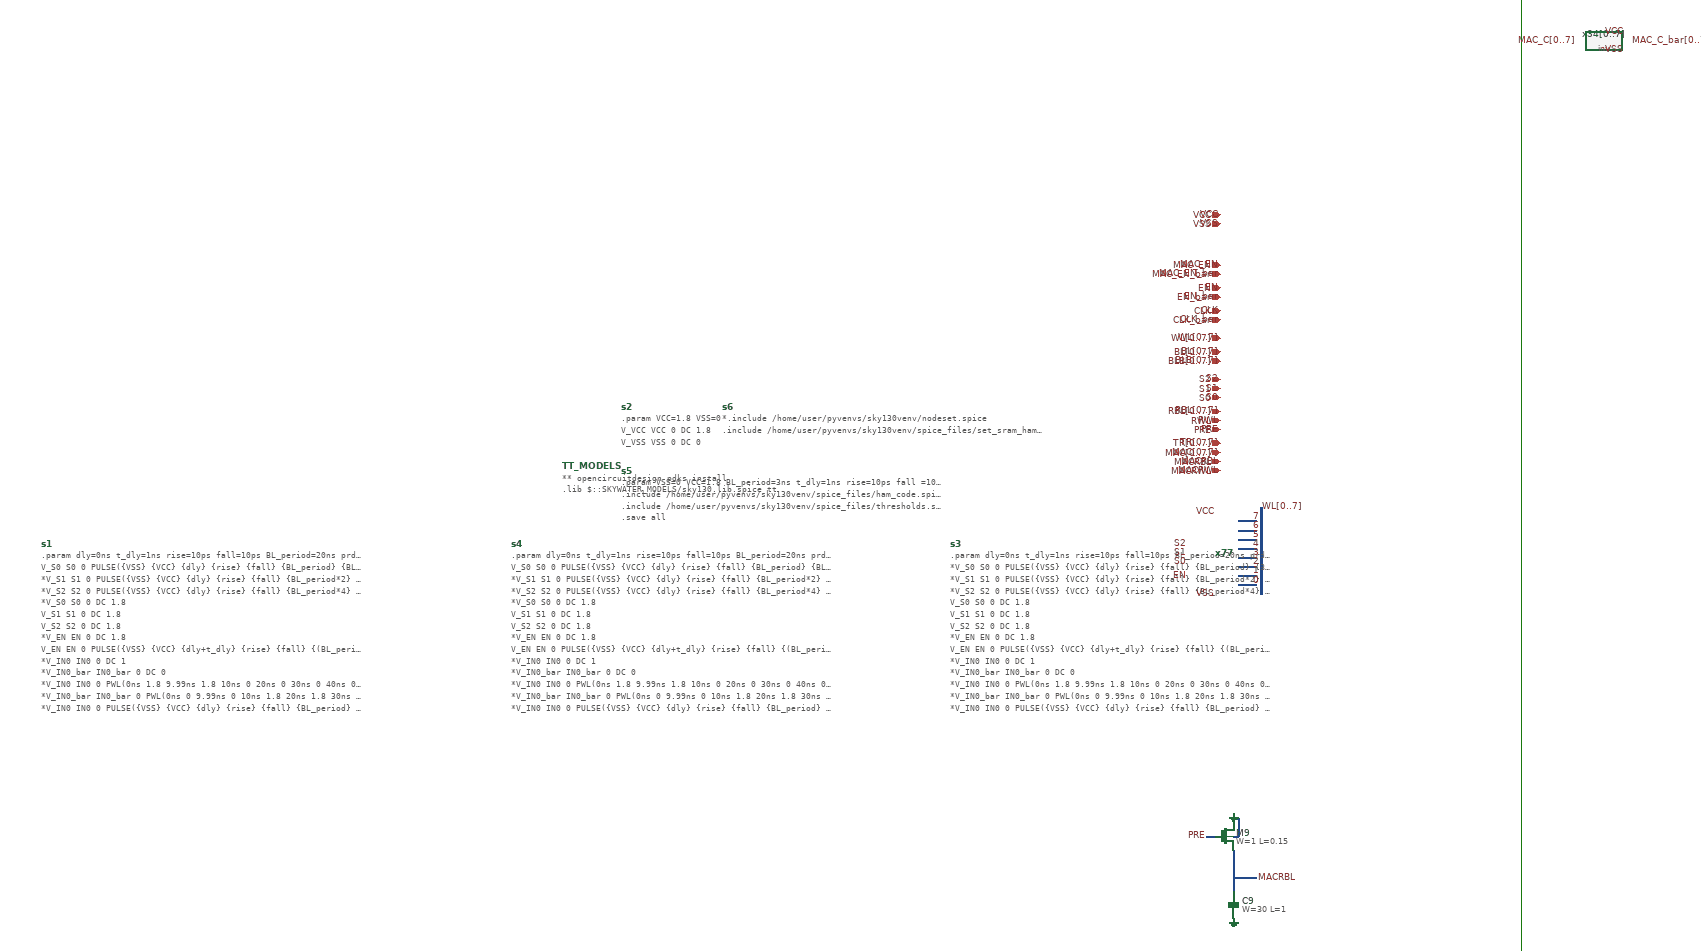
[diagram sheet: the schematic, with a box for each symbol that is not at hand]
v {xschem version=3.4.8RC file_version=1.3}
G {}
K {}
V {}
S {}
F {}
E {}
B 2 -940 -3380 -140 -2980 {flags=graph
y1=-0.027
y2=1.9
ypos1=0.4549552
ypos2=2.2583164
divy=5
subdivy=1
unity=1
x1=1.305e-08
x2=1.0005e-07
divx=5
subdivx=1
xlabmag=1.0
ylabmag=1.0
dataset=-1
unitx=1
logx=0
logy=0
rawfile=$netlist_dir/ham_real_PART1&2.raw
autoload=0
digital=1
legend=1
sim_type=tran
color="4 5 6 7 8 9 10 11 12 13 14 15 16 17 18 19 20"
node="en
pre
rwl
macrwl
clk
mac_en
ROW1;xsram8.q,xsram7.q,xsram6.q,xsram5.q,xsram4.q,xsram3.q,xsram2.q,xsram1.q
ROW2;xsram16.q,xsram15.q,xsram14.q,xsram13.q,xsram12.q,xsram11.q,xsram10.q,xsram9.q
ROW3;xsram24.q,xsram23.q,xsram22.q,xsram21.q,xsram20.q,xsram19.q,xsram18.q,xsram17.q
ROW4;xsram32.q,xsram31.q,xsram30.q,xsram29.q,xsram28.q,xsram27.q,xsram26.q,xsram25.q
ROW5;xsram40.q,xsram39.q,xsram38.q,xsram37.q,xsram36.q,xsram35.q,xsram34.q,xsram33.q
ROW6;xsram48.q,xsram47.q,xsram46.q,xsram45.q,xsram44.q,xsram43.q,xsram42.q,xsram41.q
ROW7;xsram56.q,xsram55.q,xsram54.q,xsram53.q,xsram52.q,xsram51.q,xsram50.q,xsram49.q
ROW8;xsram64.q,xsram63.q,xsram62.q,xsram61.q,xsram60.q,xsram59.q,xsram58.q,xsram57.q
ROW9;xsram_ham8.q,xsram_ham7.q,xsram_ham6.q,xsram_ham5.q,xsram_ham4.q,xsram_ham3.q,xsram_ham2.q,xsram_ham1.q
mac;mac_c7,mac_c6,mac_c5,mac_c4,mac_c3,mac_c2,mac_c1,mac_c0
mac_bar;mac_c_bar7,mac_c_bar6,mac_c_bar5,mac_c_bar4,mac_c_bar3,mac_c_bar2,mac_c_bar1,mac_c_bar0"}
B 2 -1760 -2440 -960 -2040 {flags=graph,unlocked
y1=-0.027
y2=1.9
ypos1=-0.027
ypos2=1.9
divy=5
subdivy=1
unity=1
x1=1.305e-08
x2=1.0005e-07
divx=5
subdivx=1
xlabmag=1.0
ylabmag=1.0
dataset=-1
unitx=1
logx=0
logy=0
rawfile=$netlist_dir/ham_real_PART1&2.raw
autoload=0
digital=1
color="4 5 6 7 8 9 10 11 7 7 7 7"
node="bl7
bl6
bl5
bl4
bl3
bl2
bl1
bl0


blb3
blb2
blb1
blb0"
hilight_wave=-1}
B 2 -1760 -2910 -960 -2510 {flags=graph
y1=0
y2=2
ypos1=0
ypos2=2
divy=5
subdivy=1
unity=1
x1=1.305e-08
x2=1.0005e-07
divx=5
subdivx=1
xlabmag=1.0
ylabmag=1.0
node="S;s2,s1,s0
en
pre
rwl
clk
mac_en
macrwl"
color="4 5 6 7 8 9 10"
dataset=-1
unitx=1
logx=0
logy=0
hilight_wave=4
digital=1
rawfile=$netlist_dir/ham_real_PART1&2.raw}
B 2 -1760 -3380 -960 -2980 {flags=graph
y1=-0.059
y2=1.9
ypos1=-0.027
ypos2=1.9
divy=5
subdivy=1
unity=1
x1=1.305e-08
x2=1.0005e-07
divx=5
subdivx=1
xlabmag=1.0
ylabmag=1.0
dataset=-1
unitx=1
logx=0
logy=0
rawfile=$netlist_dir/ham_real_PART1&2.raw
autoload=0
digital=1
hilight_wave=-1
sim_type=tran
color="4 7 7 9 9 6 6 11 11 5 5 8 8 20 20 21 21"
node="clk
x17.net1_1
x17.net1_0
x18.net1_1
x18.net1_0
x19.net1_1
x19.net1_0
x20.net1_1
x20.net1_0
x79.net1_1
x79.net1_0
x78.net1_1
x78.net1_0
x80.net1_1
x80.net1_0
x81.net1_1
x81.net1_0"}
B 2 -940 -2440 -140 -2040 {flags=graph
y1=-0.052
y2=1.9
ypos1=-0.027
ypos2=1.9
divy=5
subdivy=1
unity=1
x1=1.305e-08
x2=1.0005e-07
divx=5
subdivx=1
xlabmag=1.0
ylabmag=1.0
dataset=-1
unitx=1
logx=0
logy=0
rawfile=$netlist_dir/ham_real_PART1&2.raw
autoload=0
digital=1
hilight_wave=6
node="S;s2,s1,s0
en
pre
rwl
clk
mac_en
macrwl"
sim_type=tran
color="4 5 6 7 8 9 10"}
B 2 -930 -3810 -130 -3410 {flags=graph
y1=-0.31
y2=1.8
ypos1=-0.027
ypos2=1.9
divy=5
subdivy=1
unity=1
x1=1.305e-08
x2=1.0005e-07
divx=5
subdivx=1
xlabmag=1.0
ylabmag=1.0
dataset=-1
unitx=1
logx=0
logy=0
rawfile=$netlist_dir/ham_real_PART1&2.raw
autoload=0
digital=0
hilight_wave=0
sim_type=tran
color="4 5"
node="xmac_dec8.x1.x1.out+
xmac_dec8.x1.x1.out-"}
B 2 -940 -2910 -140 -2510 {flags=graph
y1=1.5728868
y2=1.9000425
ypos1=-0.027
ypos2=1.9
divy=5
subdivy=1
unity=1
x1=1.305e-08
x2=1.0005e-07
divx=5
subdivx=1
xlabmag=1.0
ylabmag=1.0
dataset=-1
unitx=1
logx=0
logy=0
rawfile=$netlist_dir/ham_real_PART1&2.raw
autoload=0
digital=0
hilight_wave=11
sim_type=tran
color="4 5 6 7 8 9 10 11 12 13 13 13 13 13 13 13 13 13"
node="rbl7
rbl6
rbl5
rbl4
rbl3
rbl2
rbl1
rbl0
macrbl
clk

tr7
tr6
tr5
tr4
tr3
tr2
tr1
tr0"}
B 2 -930 -4210 -130 -3810 {flags=graph
y1=-0.31
y2=1.8
ypos1=-0.027
ypos2=1.9
divy=5
subdivy=1
unity=1
x1=1.305e-08
x2=1.0005e-07
divx=5
subdivx=1
xlabmag=1.0
ylabmag=1.0
dataset=-1
unitx=1
logx=0
logy=0
rawfile=$netlist_dir/ham_real_PART1&2.raw
autoload=0
digital=0
hilight_wave=0
sim_type=tran
color="4 5"
node="xmac_dec8.x1.x2.out+
xmac_dec8.x1.x2.out-"}
B 4 770 -3310 3160 -200 {fill=false}
N 200 -1670 200 -1480 {lab=WL[0..7]
bus=true}
N 150 -1640 190 -1640 {lab=WL7}
N 150 -1620 190 -1620 {lab=WL6}
N 150 -1600 190 -1600 {lab=WL5}
N 150 -1580 190 -1580 {lab=WL4}
N 150 -1560 190 -1560 {lab=WL3}
N 150 -1540 190 -1540 {lab=WL2}
N 150 -1520 190 -1520 {lab=WL1}
N 150 -1500 190 -1500 {lab=WL0}
N 140 -920 140 -830 {lab=MACRBL}
N 140 -860 190 -860 {lab=MACRBL}
N 140 -1000 140 -980 {lab=GND}
N 140 -950 150 -950 {lab=GND}
N 150 -990 150 -950 {lab=GND}
N 140 -990 150 -990 {lab=GND}
N 80 -950 100 -950 {lab=PRE}
C {lab_pin.sym} 890 -2690 0 0 {name=p277 sig_type=std_logic lab=MAC_C[0..7]}
C {inv.sym} 950 -2690 0 0 {name=x34[0..7]}
C {lab_pin.sym} 950 -2710 0 1 {name=p278 sig_type=std_logic lab=VCC}
C {lab_pin.sym} 950 -2670 0 1 {name=p279 sig_type=std_logic lab=VSS}
C {lab_pin.sym} 1010 -2690 2 0 {name=p280 sig_type=std_logic lab=MAC_C_bar[0..7]}
C {iopin.sym} 110 -2040 0 0 {name=p7 lab=WL[0..7]}
C {lab_pin.sym} 110 -2040 0 0 {name=p18 sig_type=std_logic lab=WL[0..7]}
C {code.sym} -1330 -1760 0 0 {
name=TT_MODELS
only_toplevel=true
format="tcleval( @value )"
spice_ignore=false
value="
** opencircuitdesign pdks install
.lib $::SKYWATER_MODELS/sky130.lib.spice tt
"
spice_ignore=false
      }
C {code_shown.sym} -1200 -1890 0 0 {name=s2 only_toplevel=false spice_ignore=false value=
"
.param VCC=1.8 VSS=0

V_VCC VCC 0 DC 1.8
V_VSS VSS 0 DC 0
"}
C {iopin.sym} 110 -1950 0 0 {name=p69 lab=S2}
C {iopin.sym} 110 -1930 0 0 {name=p70 lab=S1}
C {iopin.sym} 110 -1910 0 0 {name=p71 lab=S0}
C {lab_pin.sym} 110 -1950 0 0 {name=p72 sig_type=std_logic lab=S2}
C {lab_pin.sym} 110 -1930 0 0 {name=p73 sig_type=std_logic lab=S1}
C {lab_pin.sym} 110 -1910 0 0 {name=p74 sig_type=std_logic lab=S0}
C {iopin.sym} 110 -2310 0 0 {name=p78 lab=VCC}
C {iopin.sym} 110 -2290 0 0 {name=p79 lab=VSS}
C {lab_pin.sym} 110 -2290 0 0 {name=p80 sig_type=std_logic lab=VSS}
C {lab_pin.sym} 110 -2310 0 0 {name=p81 sig_type=std_logic lab=VCC}
C {iopin.sym} 110 -2150 0 0 {name=p82 lab=EN}
C {lab_pin.sym} 110 -2150 0 0 {name=p83 sig_type=std_logic lab=EN}
C {code_shown.sym} -480 -1590 0 1 {name=s3 only_toplevel=false spice_ignore=true value=
"
.param dly=0ns t_dly=1ns rise=10ps fall=10ps BL_period=20ns prds=8 pre_time=6ns read_time=2ns write_delay=10ns 


*V_S0 S0 0 PULSE(\{VSS\} \{VCC\} \{dly\} \{rise\} \{fall\} \{BL_period\} \{BL_period*2\} \{prds\})
*V_S1 S1 0 PULSE(\{VSS\} \{VCC\} \{dly\} \{rise\} \{fall\} \{BL_period*2\} \{BL_period*4\} \{prds\})
*V_S2 S2 0 PULSE(\{VSS\} \{VCC\} \{dly\} \{rise\} \{fall\} \{BL_period*4\} \{BL_period*8\} \{prds\})

V_S0 S0 0 DC 1.8
V_S1 S1 0 DC 1.8
V_S2 S2 0 DC 1.8

*V_EN EN 0 DC 1.8
V_EN EN 0 PULSE(\{VSS\} \{VCC\} \{dly+t_dly\} \{rise\} \{fall\} \{(BL_period/2)-t_dly*2\} \{BL_period\} \{prds\})

*V_IN0 IN0 0 DC 1
*V_IN0_bar IN0_bar 0 DC 0
*V_IN0 IN0 0 PWL(0ns 1.8 9.99ns 1.8 10ns 0 20ns 0 30ns 0 40ns 0 50ns 0 60ns 0 69.99ns 0 70ns 1.8)
*V_IN0_bar IN0_bar 0 PWL(0ns 0 9.99ns 0 10ns 1.8 20ns 1.8 30ns 1.8 40ns 1.8 50ns 1.8 60ns 1.8 69.99ns 1.8 70ns 0)
*V_IN0 IN0 0 PULSE(\{VSS\} \{VCC\} \{dly\} \{rise\} \{fall\} \{BL_period\} \{BL_period*2\} \{prds\})
*V_IN0_bar IN0_bar 0 PULSE(\{VCC\} \{VSS\} \{dly\} \{rise\} \{fall\} \{BL_period\} \{BL_period*2\} \{prds\})

V_BL0 BLB0 0 PULSE(\{VSS\} \{VCC\} \{dly\} \{rise\} \{fall\} \{BL_period\} \{BL_period*2\} \{prds\})
V_BLB0 BL0 0 PULSE(\{VCC\} \{VSS\} \{dly\} \{rise\} \{fall\} \{BL_period\} \{BL_period*2\} \{prds\})

V_BL1 BLB1 0 PULSE(\{VSS\} \{VCC\} \{dly\} \{rise\} \{fall\} \{BL_period*2\} \{BL_period*4\} \{prds\})
V_BLB1 BL1 0 PULSE(\{VCC\} \{VSS\} \{dly\} \{rise\} \{fall\} \{BL_period*2\} \{BL_period*4\} \{prds\})

V_BL2 BLB2 0 PULSE(\{VSS\} \{VCC\} \{dly\} \{rise\} \{fall\} \{BL_period*4\} \{BL_period*8\} \{prds\})
V_BLB2 BL2 0 PULSE(\{VCC\} \{VSS\} \{dly\} \{rise\} \{fall\} \{BL_period*4\} \{BL_period*8\} \{prds\})

V_BL3 BLB3 0 PULSE(\{VSS\} \{VCC\} \{dly\} \{rise\} \{fall\} \{BL_period*8\} \{BL_period*16\} \{prds\})
V_BLB3 BL3 0 PULSE(\{VCC\} \{VSS\} \{dly\} \{rise\} \{fall\} \{BL_period*8\} \{BL_period*16\} \{prds\})

V_BL4 BLB4 0 PULSE(\{VSS\} \{VCC\} \{dly\} \{rise\} \{fall\} \{BL_period*16\} \{BL_period*32\} \{prds\})
V_BLB4 BL4 0 PULSE(\{VCC\} \{VSS\} \{dly\} \{rise\} \{fall\} \{BL_period*16\} \{BL_period*32\} \{prds\})

V_BL5 BLB5 0 PULSE(\{VSS\} \{VCC\} \{dly\} \{rise\} \{fall\} \{BL_period*32\} \{BL_period*64\} \{prds\})
V_BLB5 BL5 0 PULSE(\{VCC\} \{VSS\} \{dly\} \{rise\} \{fall\} \{BL_period*32\} \{BL_period*64\} \{prds\})

V_BL6 BLB6 0 PULSE(\{VSS\} \{VCC\} \{dly\} \{rise\} \{fall\} \{BL_period*64\} \{BL_period*128\} \{prds\})
V_BLB6 BL6 0 PULSE(\{VCC\} \{VSS\} \{dly\} \{rise\} \{fall\} \{BL_period*64\} \{BL_period*128\} \{prds\})

V_BL7 BLB7 0 PULSE(\{VSS\} \{VCC\} \{dly\} \{rise\} \{fall\} \{BL_period*128\} \{BL_period*256\} \{prds\})
V_BLB7 BL7 0 PULSE(\{VCC\} \{VSS\} \{dly\} \{rise\} \{fall\} \{BL_period*128\} \{BL_period*256\} \{prds\})



*V_RWL RWL 0 DC 1.8
*V_RBL RBL 0 DC 0
*V_RWL RWL 0 PULSE(\{VCC\} \{VSS\} \{write_delay+t_dly+pre_time+t_dly\} \{rise\} \{fall\} \{read_time\} \{BL_period\} \{prds\})
*V_PRE PRE 0 PULSE(\{VSS\} \{VCC\} \{write_delay+t_dly\} \{rise\} \{fall\} \{pre_time\} \{BL_period\} \{prds\})
V_RWL RWL 0 PULSE(\{VCC\} \{VSS\} \{dly + BL_period/2 + 7ns\} \{rise\} \{fall\} \{read_time\} \{BL_period\} \{prds*2\})
V_PRE PRE 0 PULSE(\{VSS\} \{VCC\} \{dly + BL_period/2\} \{rise\} \{fall\} \{pre_time\} \{BL_period\} \{prds*2\})

.tran 0.01ns \{BL_period*2*10\}
.save all

.control
run
plot Y0 Y1+2 Y2+4 Y3+6 Y4+8 Y5+10 Y6+12 Y7+14
plot EN
plot I0 I1+2 I2+4
.endc
"}
C {iopin.sym} 110 -1880 0 0 {name=p89 lab=RBL[0..7]}
C {iopin.sym} 110 -1860 0 0 {name=p90 lab=RWL}
C {lab_pin.sym} 110 -1880 0 0 {name=p91 sig_type=std_logic lab=RBL[0..7]}
C {lab_pin.sym} 110 -1860 0 0 {name=p92 sig_type=std_logic lab=RWL}
C {iopin.sym} 110 -1840 0 0 {name=p93 lab=PRE}
C {lab_pin.sym} 110 -1840 0 0 {name=p95 sig_type=std_logic lab=PRE}
C {iopin.sym} 110 -2010 0 0 {name=p17 lab=BL[0..7]}
C {lab_pin.sym} 110 -2010 0 0 {name=p26 sig_type=std_logic lab=BL[0..7]}
C {iopin.sym} 110 -1990 0 0 {name=p59 lab=BLB[0..7]}
C {lab_pin.sym} 110 -1990 0 0 {name=p60 sig_type=std_logic lab=BLB[0..7]}
C {logic gates/decoder.sym} 100 -1570 0 0 {name=x77}
C {lab_pin.sym} 40 -1590 0 0 {name=p75 sig_type=std_logic lab=S2}
C {lab_pin.sym} 40 -1570 0 0 {name=p76 sig_type=std_logic lab=S1}
C {lab_pin.sym} 40 -1550 0 0 {name=p77 sig_type=std_logic lab=S0}
C {lab_pin.sym} 40 -1520 0 0 {name=p84 sig_type=std_logic lab=EN}
C {lab_pin.sym} 100 -1660 0 0 {name=p85 sig_type=std_logic lab=VCC}
C {lab_pin.sym} 100 -1480 0 0 {name=p86 sig_type=std_logic lab=VSS}
C {code_shown.sym} -1440 -1590 0 1 {name=s4 only_toplevel=false spice_ignore=true value=
"
.param dly=0ns t_dly=1ns rise=10ps fall=10ps BL_period=20ns prds=10 pre_time=6ns read_time=2ns write_delay=10ns 


V_S0 S0 0 PULSE(\{VSS\} \{VCC\} \{dly\} \{rise\} \{fall\} \{BL_period\} \{BL_period*2\} \{prds\})
*V_S1 S1 0 PULSE(\{VSS\} \{VCC\} \{dly\} \{rise\} \{fall\} \{BL_period*2\} \{BL_period*4\} \{prds\})
*V_S2 S2 0 PULSE(\{VSS\} \{VCC\} \{dly\} \{rise\} \{fall\} \{BL_period*4\} \{BL_period*8\} \{prds\})

*V_S0 S0 0 DC 1.8
V_S1 S1 0 DC 1.8
V_S2 S2 0 DC 1.8

*V_EN EN 0 DC 1.8
V_EN EN 0 PULSE(\{VSS\} \{VCC\} \{dly+t_dly\} \{rise\} \{fall\} \{(BL_period/2)-t_dly*2\} \{BL_period\} \{prds\})

*V_IN0 IN0 0 DC 1
*V_IN0_bar IN0_bar 0 DC 0
*V_IN0 IN0 0 PWL(0ns 1.8 9.99ns 1.8 10ns 0 20ns 0 30ns 0 40ns 0 50ns 0 60ns 0 69.99ns 0 70ns 1.8)
*V_IN0_bar IN0_bar 0 PWL(0ns 0 9.99ns 0 10ns 1.8 20ns 1.8 30ns 1.8 40ns 1.8 50ns 1.8 60ns 1.8 69.99ns 1.8 70ns 0)
*V_IN0 IN0 0 PULSE(\{VSS\} \{VCC\} \{dly\} \{rise\} \{fall\} \{BL_period\} \{BL_period*2\} \{prds\})
*V_IN0_bar IN0_bar 0 PULSE(\{VCC\} \{VSS\} \{dly\} \{rise\} \{fall\} \{BL_period\} \{BL_period*2\} \{prds\})

V_BL0 BLB0 0 PWL(0ns 1.8 20ns 1.8 40ns 1.8 59.99ns 1.8 60ns 0 80ns 0 99.99ns 0 100ns 1.8 119.99ns 1.8 120ns 0 140ns 0)
V_BLB0 BL0 0 PWL(0ns 0 20ns 0 40ns 0 59.99ns 0 60ns 1.8 80ns 1.8 99.99ns 1.8 100ns 0 119.99ns 0 120ns 1.8 140ns 1.8)

V_BL1 BLB1 0 PWL(0ns 1.8 20ns 1.8 40ns 1.8 59.99ns 1.8 60ns 0 80ns 0 99.99ns 0 100ns 1.8 119.99ns 1.8 120ns 0 140ns 0)
V_BLB1 BL1 0 PWL(0ns 0 20ns 0 40ns 0 59.99ns 0 60ns 1.8 80ns 1.8 99.99ns 1.8 100ns 0 119.99ns 0 120ns 1.8 140ns 1.8)

V_BL2 BLB2 0 PWL(0ns 1.8 20ns 1.8 40ns 1.8 59.99ns 1.8 60ns 0 80ns 0 99.99ns 0 100ns 1.8 119.99ns 1.8 120ns 0 140ns 0)
V_BLB2 BL2 0 PWL(0ns 0 20ns 0 40ns 0 59.99ns 0 60ns 1.8 80ns 1.8 99.99ns 1.8 100ns 0 119.99ns 0 120ns 1.8 140ns 1.8)

V_BL3 BLB3 0 PWL(0ns 1.8 20ns 1.8 40ns 1.8 59.99ns 1.8 60ns 0 80ns 0 99.99ns 0 100ns 1.8 119.99ns 1.8 120ns 0 140ns 0)
V_BLB3 BL3 0 PWL(0ns 0 20ns 0 40ns 0 59.99ns 0 60ns 1.8 80ns 1.8 99.99ns 1.8 100ns 0 119.99ns 0 120ns 1.8 140ns 1.8)

V_BL4 BLB4 0 PWL(0ns 1.8 20ns 1.8 40ns 1.8 59.99ns 1.8 60ns 0 80ns 0 99.99ns 0 100ns 1.8 119.99ns 1.8 120ns 0 140ns 0)
V_BLB4 BL4 0 PWL(0ns 0 20ns 0 40ns 0 59.99ns 0 60ns 1.8 80ns 1.8 99.99ns 1.8 100ns 0 119.99ns 0 120ns 1.8 140ns 1.8)

V_BL5 BLB5 0 PWL(0ns 1.8 20ns 1.8 40ns 1.8 59.99ns 1.8 60ns 0 80ns 0 99.99ns 0 100ns 1.8 119.99ns 1.8 120ns 0 140ns 0)
V_BLB5 BL5 0 PWL(0ns 0 20ns 0 40ns 0 59.99ns 0 60ns 1.8 80ns 1.8 99.99ns 1.8 100ns 0 119.99ns 0 120ns 1.8 140ns 1.8)

V_BL6 BLB6 0 PWL(0ns 1.8 20ns 1.8 40ns 1.8 59.99ns 1.8 60ns 0 80ns 0 99.99ns 0 100ns 1.8 119.99ns 1.8 120ns 0 140ns 0)
V_BLB6 BL6 0 PWL(0ns 0 20ns 0 40ns 0 59.99ns 0 60ns 1.8 80ns 1.8 99.99ns 1.8 100ns 0 119.99ns 0 120ns 1.8 140ns 1.8)

V_BL7 BLB7 0 PWL(0ns 1.8 20ns 1.8 40ns 1.8 59.99ns 1.8 60ns 0 80ns 0 99.99ns 0 100ns 1.8 119.99ns 1.8 120ns 0 140ns 0)
V_BLB7 BL7 0 PWL(0ns 0 20ns 0 40ns 0 59.99ns 0 60ns 1.8 80ns 1.8 99.99ns 1.8 100ns 0 119.99ns 0 120ns 1.8 140ns 1.8)



*V_RWL RWL 0 DC 1.8
*V_RBL RBL 0 DC 0
*V_RWL RWL 0 PULSE(\{VCC\} \{VSS\} \{write_delay+t_dly+pre_time+t_dly\} \{rise\} \{fall\} \{read_time\} \{BL_period\} \{prds\})
*V_PRE PRE 0 PULSE(\{VSS\} \{VCC\} \{write_delay+t_dly\} \{rise\} \{fall\} \{pre_time\} \{BL_period\} \{prds\})
V_RWL RWL 0 PULSE(\{VCC\} \{VSS\} \{dly + BL_period/2 + 7ns\} \{rise\} \{fall\} \{read_time\} \{BL_period\} \{prds\})
V_PRE PRE 0 PULSE(\{VSS\} \{VCC\} \{dly + BL_period/2\} \{rise\} \{fall\} \{pre_time\} \{BL_period\} \{prds\})

.tran 0.01ns \{BL_period*10\}
.save all

.control
run
plot Y0 Y1+2 Y2+4 Y3+6 Y4+8 Y5+10 Y6+12 Y7+14
plot EN
plot I0 I1+2 I2+4
.endc
"}
C {lab_pin.sym} 200 -1670 0 1 {name=p8 sig_type=std_logic lab=WL[0..7]}
C {bus_tap.sym} 200 -1590 3 1 {name=l21 lab=4}
C {bus_tap.sym} 200 -1570 3 1 {name=l22 lab=3}
C {bus_tap.sym} 200 -1550 3 1 {name=l23 lab=2}
C {bus_tap.sym} 200 -1510 3 1 {name=l24 lab=0}
C {bus_tap.sym} 200 -1530 3 1 {name=l25 lab=1}
C {bus_tap.sym} 200 -1610 3 1 {name=l19 lab=5}
C {bus_tap.sym} 200 -1630 3 1 {name=l20 lab=6}
C {bus_tap.sym} 200 -1650 3 1 {name=l26 lab=7}
C {iopin.sym} 110 -2100 0 0 {name=p131 lab=CLK}
C {lab_pin.sym} 110 -2100 0 0 {name=p132 sig_type=std_logic lab=CLK}
C {iopin.sym} 110 -2080 0 0 {name=p133 lab=CLK_bar}
C {lab_pin.sym} 110 -2080 0 0 {name=p134 sig_type=std_logic lab=CLK_bar}
C {iopin.sym} 110 -2130 0 0 {name=p135 lab=EN_bar}
C {lab_pin.sym} 110 -2130 0 0 {name=p136 lab=EN_bar}
C {lab_pin.sym} 110 -1810 0 0 {name=p145 sig_type=std_logic lab=TR[0..7]}
C {iopin.sym} 110 -1810 0 0 {name=p146 lab=TR[0..7]}
C {lab_pin.sym} 110 -1790 0 0 {name=p210 sig_type=std_logic lab=MAC[0..7]}
C {iopin.sym} 110 -1790 0 0 {name=p211 lab=MAC[0..7]}
C {iopin.sym} 110 -1770 0 0 {name=p212 lab=MACRBL}
C {lab_pin.sym} 110 -1770 0 0 {name=p213 sig_type=std_logic lab=MACRBL}
C {iopin.sym} 110 -1750 0 0 {name=p254 lab=MACRWL}
C {lab_pin.sym} 110 -1750 0 0 {name=p255 sig_type=std_logic lab=MACRWL}
C {sky130_fd_pr/cap_mim_m3_1.sym} 140 -800 0 0 {name=C9 model=cap_mim_m3_1 W=30 L=1 MF=1 spiceprefix=X}
C {gnd.sym} 140 -1000 2 0 {name=l41 lab=GND}
C {sky130_fd_pr/nfet_01v8.sym} 120 -950 2 1 {name=M9
W=1
L=0.15
nf=1 
mult=1
ad="expr('int((@nf + 1)/2) * @W / @nf * 0.29')"
pd="expr('2*int((@nf + 1)/2) * (@W / @nf + 0.29)')"
as="expr('int((@nf + 2)/2) * @W / @nf * 0.29')"
ps="expr('2*int((@nf + 2)/2) * (@W / @nf + 0.29)')"
nrd="expr('0.29 / @W ')" nrs="expr('0.29 / @W ')"
sa=0 sb=0 sd=0
model=nfet_01v8
spiceprefix=X
}
C {gnd.sym} 140 -770 0 1 {name=l42 lab=GND}
C {lab_pin.sym} 80 -950 0 0 {name=p256 sig_type=std_logic lab=PRE}
C {lab_pin.sym} 190 -860 0 1 {name=p257 sig_type=std_logic lab=MACRBL}
C {code_shown.sym} -2470 -1590 0 1 {name=s1 only_toplevel=false spice_ignore=true value=
"
.param dly=0ns t_dly=1ns rise=10ps fall=10ps BL_period=20ns prds=10 pre_time=6ns read_time=2ns write_delay=10ns 


V_S0 S0 0 PULSE(\{VSS\} \{VCC\} \{dly\} \{rise\} \{fall\} \{BL_period\} \{BL_period*2\} \{prds\})
*V_S1 S1 0 PULSE(\{VSS\} \{VCC\} \{dly\} \{rise\} \{fall\} \{BL_period*2\} \{BL_period*4\} \{prds\})
*V_S2 S2 0 PULSE(\{VSS\} \{VCC\} \{dly\} \{rise\} \{fall\} \{BL_period*4\} \{BL_period*8\} \{prds\})

*V_S0 S0 0 DC 1.8
V_S1 S1 0 DC 1.8
V_S2 S2 0 DC 1.8

*V_EN EN 0 DC 1.8
V_EN EN 0 PULSE(\{VSS\} \{VCC\} \{dly+t_dly\} \{rise\} \{fall\} \{(BL_period/2)-t_dly*2\} \{BL_period\} \{prds\})

*V_IN0 IN0 0 DC 1
*V_IN0_bar IN0_bar 0 DC 0
*V_IN0 IN0 0 PWL(0ns 1.8 9.99ns 1.8 10ns 0 20ns 0 30ns 0 40ns 0 50ns 0 60ns 0 69.99ns 0 70ns 1.8)
*V_IN0_bar IN0_bar 0 PWL(0ns 0 9.99ns 0 10ns 1.8 20ns 1.8 30ns 1.8 40ns 1.8 50ns 1.8 60ns 1.8 69.99ns 1.8 70ns 0)
*V_IN0 IN0 0 PULSE(\{VSS\} \{VCC\} \{dly\} \{rise\} \{fall\} \{BL_period\} \{BL_period*2\} \{prds\})
*V_IN0_bar IN0_bar 0 PULSE(\{VCC\} \{VSS\} \{dly\} \{rise\} \{fall\} \{BL_period\} \{BL_period*2\} \{prds\})

V_BL0 BLB0 0 PWL(0ns 1.8 20ns 1.8 40ns 1.8 59.99ns 1.8 60ns 0 80ns 0 99.99ns 0 100ns 1.8 119.99ns 1.8 120ns 0 140ns 0)
V_BLB0 BL0 0 PWL(0ns 0 20ns 0 40ns 0 59.99ns 0 60ns 1.8 80ns 1.8 99.99ns 1.8 100ns 0 119.99ns 0 120ns 1.8 140ns 1.8)

V_BL1 BLB1 0 PWL(0ns 1.8 20ns 1.8 40ns 1.8 59.99ns 1.8 60ns 0 80ns 0 99.99ns 0 100ns 1.8 119.99ns 1.8 120ns 0 140ns 0)
V_BLB1 BL1 0 PWL(0ns 0 20ns 0 40ns 0 59.99ns 0 60ns 1.8 80ns 1.8 99.99ns 1.8 100ns 0 119.99ns 0 120ns 1.8 140ns 1.8)

V_BL2 BLB2 0 PWL(0ns 1.8 20ns 1.8 40ns 1.8 59.99ns 1.8 60ns 0 80ns 0 99.99ns 0 100ns 1.8 119.99ns 1.8 120ns 0 140ns 0)
V_BLB2 BL2 0 PWL(0ns 0 20ns 0 40ns 0 59.99ns 0 60ns 1.8 80ns 1.8 99.99ns 1.8 100ns 0 119.99ns 0 120ns 1.8 140ns 1.8)

V_BL3 BLB3 0 PWL(0ns 1.8 20ns 1.8 40ns 1.8 59.99ns 1.8 60ns 0 80ns 0 99.99ns 0 100ns 1.8 119.99ns 1.8 120ns 0 140ns 0)
V_BLB3 BL3 0 PWL(0ns 0 20ns 0 40ns 0 59.99ns 0 60ns 1.8 80ns 1.8 99.99ns 1.8 100ns 0 119.99ns 0 120ns 1.8 140ns 1.8)

V_BL4 BLB4 0 PWL(0ns 1.8 20ns 1.8 40ns 1.8 59.99ns 1.8 60ns 0 80ns 0 99.99ns 0 100ns 1.8 119.99ns 1.8 120ns 0 140ns 0)
V_BLB4 BL4 0 PWL(0ns 0 20ns 0 40ns 0 59.99ns 0 60ns 1.8 80ns 1.8 99.99ns 1.8 100ns 0 119.99ns 0 120ns 1.8 140ns 1.8)

V_BL5 BLB5 0 PWL(0ns 1.8 20ns 1.8 40ns 1.8 59.99ns 1.8 60ns 0 80ns 0 99.99ns 0 100ns 1.8 119.99ns 1.8 120ns 0 140ns 0)
V_BLB5 BL5 0 PWL(0ns 0 20ns 0 40ns 0 59.99ns 0 60ns 1.8 80ns 1.8 99.99ns 1.8 100ns 0 119.99ns 0 120ns 1.8 140ns 1.8)

V_BL6 BLB6 0 PWL(0ns 1.8 20ns 1.8 40ns 1.8 59.99ns 1.8 60ns 0 80ns 0 99.99ns 0 100ns 1.8 119.99ns 1.8 120ns 0 140ns 0)
V_BLB6 BL6 0 PWL(0ns 0 20ns 0 40ns 0 59.99ns 0 60ns 1.8 80ns 1.8 99.99ns 1.8 100ns 0 119.99ns 0 120ns 1.8 140ns 1.8)

V_BL7 BLB7 0 PWL(0ns 1.8 20ns 1.8 40ns 1.8 59.99ns 1.8 60ns 0 80ns 0 99.99ns 0 100ns 1.8 119.99ns 1.8 120ns 0 140ns 0)
V_BLB7 BL7 0 PWL(0ns 0 20ns 0 40ns 0 59.99ns 0 60ns 1.8 80ns 1.8 99.99ns 1.8 100ns 0 119.99ns 0 120ns 1.8 140ns 1.8)



*V_RWL RWL 0 DC 1.8
*V_RBL RBL 0 DC 0
*V_RWL RWL 0 PULSE(\{VCC\} \{VSS\} \{write_delay+t_dly+pre_time+t_dly\} \{rise\} \{fall\} \{read_time\} \{BL_period\} \{prds\})
*V_PRE PRE 0 PULSE(\{VSS\} \{VCC\} \{write_delay+t_dly\} \{rise\} \{fall\} \{pre_time\} \{BL_period\} \{prds\})
V_RWL RWL 0 PULSE(\{VCC\} \{VSS\} \{dly + BL_period/2 + 7ns\} \{rise\} \{fall\} \{read_time\} \{BL_period\} \{prds\})
V_PRE PRE 0 PULSE(\{VSS\} \{VCC\} \{dly + BL_period/2\} \{rise\} \{fall\} \{pre_time\} \{BL_period\} \{prds\})

.tran 0.01ns \{BL_period*10\}
.save all

.control
run
plot Y0 Y1+2 Y2+4 Y3+6 Y4+8 Y5+10 Y6+12 Y7+14
plot EN
plot I0 I1+2 I2+4
.endc
"}
C {iopin.sym} 110 -2200 0 0 {name=p281 lab=MAC_EN}
C {lab_pin.sym} 110 -2200 0 0 {name=p282 sig_type=std_logic lab=MAC_EN}
C {iopin.sym} 110 -2180 0 0 {name=p283 lab=MAC_EN_bar}
C {lab_pin.sym} 110 -2180 0 0 {name=p284 lab=MAC_EN_bar}
C {code_shown.sym} -1200 -1750 0 0 {name=s5 only_toplevel=false value=
"
.param VSS=0 VCC=1.8 BL_period=3ns t_dly=1ns rise=10ps fall =10ps rwl_time=0.5ns pre_time=6ns clk_period=30ns

.include "/home/user/pyvenvs/sky130venv/spice_files/ham_code.spice"
.include "/home/user/pyvenvs/sky130venv/spice_files/thresholds.spice"
.save all

"}
C {code_shown.sym} -980 -1890 0 0 {name=s6 only_toplevel=false spice_ignore=false value=
"
*.include "/home/user/pyvenvs/sky130venv/nodeset.spice"
.include "/home/user/pyvenvs/sky130venv/spice_files/set_sram_ham_small.spice"
"}
C {launcher.sym} -60 -2480 0 0 {name=h5
descr="load waves" 
tclcommand="xschem raw_read $netlist_dir/ham_real_PART1&2.raw tran"
}
